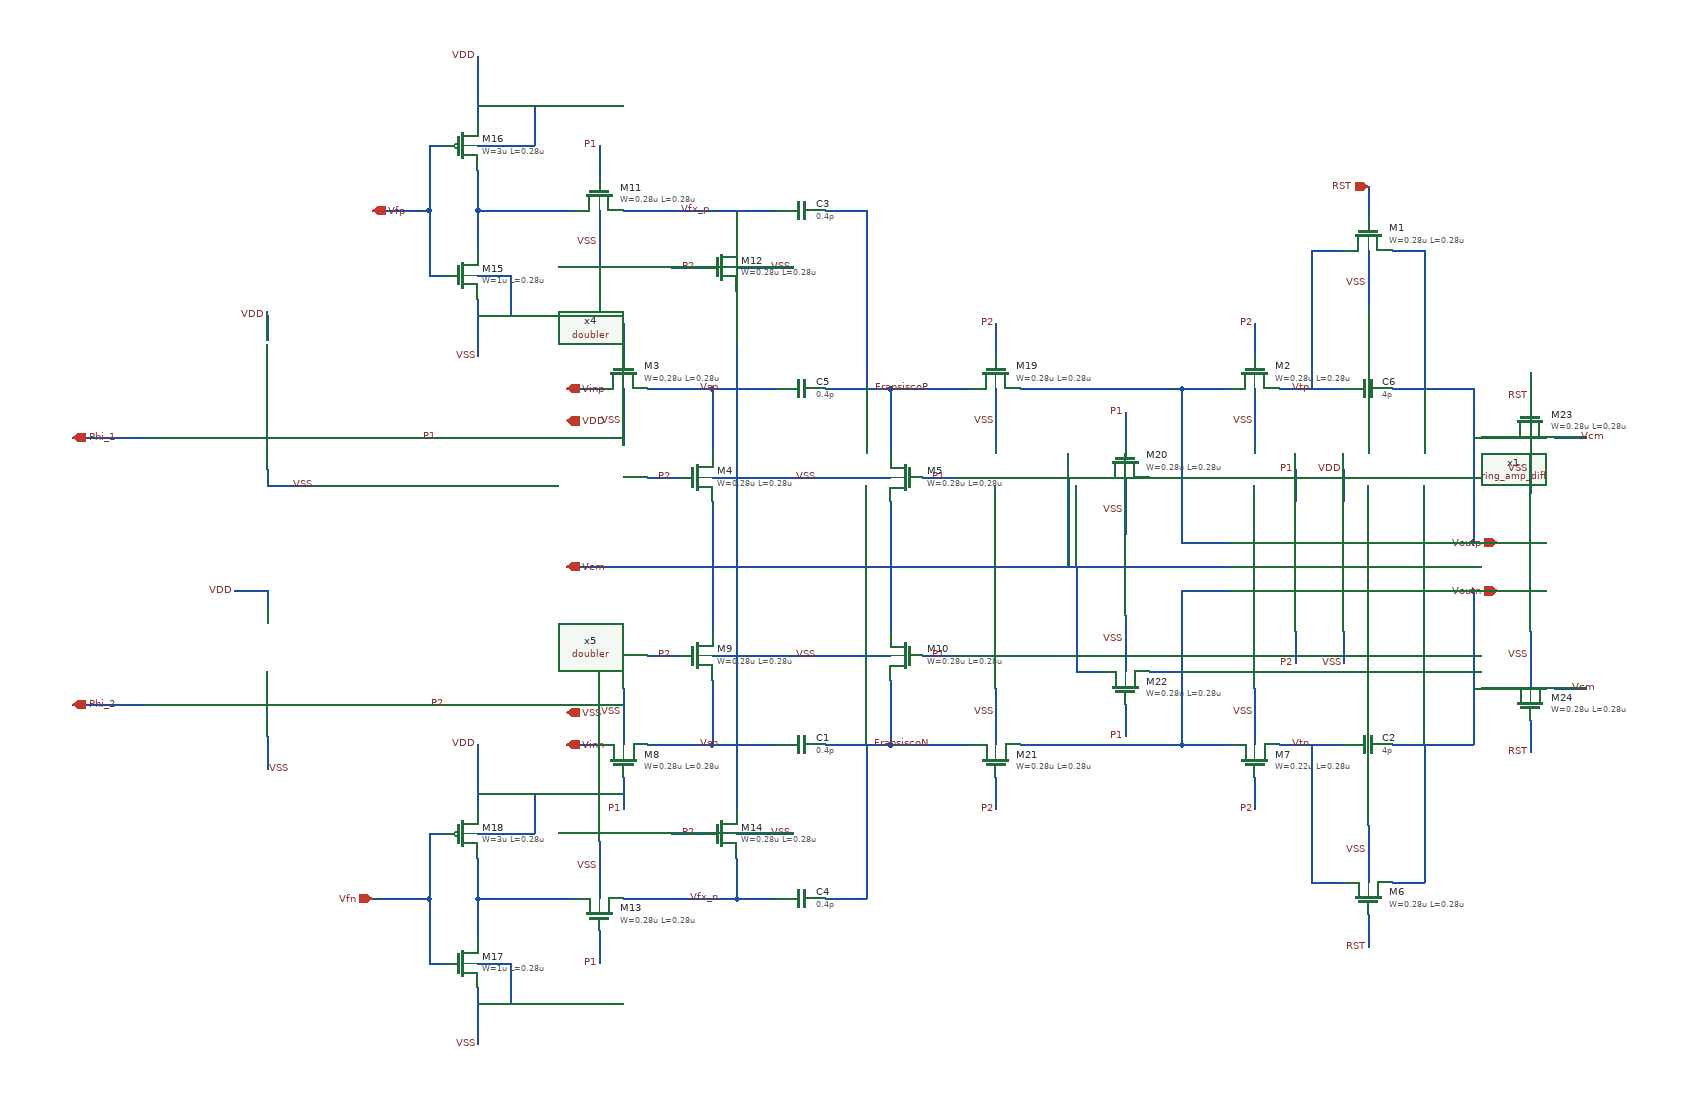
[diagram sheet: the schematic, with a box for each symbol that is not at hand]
v {xschem version=3.4.8RC file_version=1.3}
G {}
K {}
V {}
S {}
F {}
E {}
N 1190 -770 1190 -730 {lab=P1}
N 1250 -770 1250 -730 {lab=VDD}
N 1190 -570 1190 -530 {lab=P2}
N 1250 -570 1250 -530 {lab=VSS}
N 530 -650 1110 -650 {lab=Vcm}
N 470 -730 470 -690 {lab=Vcm}
N 690 -730 690 -690 {lab=Vcm}
N 470 -870 470 -790 {lab=Vsp}
N 690 -830 690 -790 {lab=FransiscoP}
N 610 -870 690 -870 {lab=FransiscoP}
N 470 -870 550 -870 {lab=Vsp}
N 390 -760 430 -760 {lab=P2}
N 390 -870 470 -870 {lab=Vsp}
N 290 -870 330 -870 {lab=Vinp}
N 360 -870 360 -800 {lab=VSS}
N 360 -950 360 -910 {lab=P1}
N 730 -760 770 -760 {lab=P1}
N 1140 -870 1140 -800 {lab=VSS}
N 690 -870 770 -870 {lab=FransiscoP}
N 1010 -870 1050 -870 {lab=#net1}
N 1050 -790 1050 -680 {lab=#net1}
N 470 -690 470 -650 {lab=Vcm}
N 690 -690 690 -650 {lab=Vcm}
N 690 -870 690 -830 {lab=FransiscoP}
N 1050 -870 1050 -790 {lab=#net1}
N 1050 -870 1090 -870 {lab=#net1}
N 1170 -870 1250 -870 {lab=Vtp}
N 1210 -1040 1210 -870 {lab=Vtp}
N 1210 -1040 1240 -1040 {lab=Vtp}
N 1140 -950 1140 -910 {lab=P2}
N 1280 -1120 1280 -1080 {lab=RST}
N 1370 -680 1410 -680 {lab=Voutp}
N 1410 -870 1410 -680 {lab=Voutp}
N 1330 -870 1410 -870 {lab=Voutp}
N 1310 -870 1330 -870 {lab=Voutp}
N 1240 -1040 1250 -1040 {lab=Vtp}
N 1310 -1040 1350 -1040 {lab=Voutp}
N 1350 -1040 1350 -870 {lab=Voutp}
N 1090 -870 1110 -870 {lab=#net1}
N 470 -760 690 -760 {lab=VSS}
N 470 -610 470 -570 {lab=Vcm}
N 690 -610 690 -570 {lab=Vcm}
N 470 -510 470 -430 {lab=Vsn}
N 690 -510 690 -470 {lab=FransiscoN}
N 610 -430 690 -430 {lab=FransiscoN}
N 470 -430 550 -430 {lab=Vsn}
N 390 -540 430 -540 {lab=P2}
N 390 -430 470 -430 {lab=Vsn}
N 290 -430 330 -430 {lab=Vinn}
N 360 -500 360 -430 {lab=VSS}
N 360 -390 360 -350 {lab=P1}
N 730 -540 770 -540 {lab=P1}
N 1140 -500 1140 -430 {lab=VSS}
N 690 -430 770 -430 {lab=FransiscoN}
N 1050 -620 1050 -510 {lab=#net2}
N 470 -650 470 -610 {lab=Vcm}
N 690 -650 690 -610 {lab=Vcm}
N 690 -470 690 -430 {lab=FransiscoN}
N 1050 -510 1050 -430 {lab=#net2}
N 1050 -430 1090 -430 {lab=#net2}
N 1170 -430 1250 -430 {lab=Vtn}
N 1210 -430 1210 -260 {lab=Vtn}
N 1210 -260 1240 -260 {lab=Vtn}
N 1140 -390 1140 -350 {lab=P2}
N 1280 -220 1280 -180 {lab=RST}
N 1370 -620 1410 -620 {lab=Voutn}
N 1410 -620 1410 -430 {lab=Voutn}
N 1330 -430 1410 -430 {lab=Voutn}
N 1310 -430 1330 -430 {lab=Voutn}
N 1240 -260 1250 -260 {lab=Vtn}
N 1310 -260 1350 -260 {lab=Voutn}
N 1350 -430 1350 -260 {lab=Voutn}
N 1090 -430 1110 -430 {lab=#net2}
N 470 -540 690 -540 {lab=VSS}
N 1410 -680 1440 -680 {lab=Voutp}
N 1410 -620 1440 -620 {lab=Voutn}
N 1280 -1040 1280 -970 {lab=VSS}
N 1280 -330 1280 -260 {lab=VSS}
N 180 -1280 180 -1240 {lab=VDD}
N 180 -950 180 -910 {lab=VSS}
N 50 -1090 120 -1090 {lab=Vfp}
N 360 -1090 440 -1090 {lab=Vfx_p}
N 260 -1090 300 -1090 {lab=#net3}
N 330 -1090 330 -1020 {lab=VSS}
N 330 -1170 330 -1130 {lab=P1}
N 420 -1020 460 -1020 {lab=P2}
N 440 -1090 550 -1090 {lab=Vfx_p}
N 500 -1090 500 -1050 {lab=Vfx_p}
N 50 -240 120 -240 {lab=Vfn}
N 260 -240 300 -240 {lab=#net4}
N 330 -310 330 -240 {lab=VSS}
N 330 -200 330 -160 {lab=P1}
N 420 -320 460 -320 {lab=P2}
N 500 -290 500 -240 {lab=Vfx_n}
N 500 -240 550 -240 {lab=Vfx_n}
N 500 -240 550 -240 {lab=Vfx_n}
N 360 -240 500 -240 {lab=Vfx_n}
N 500 -320 570 -320 {lab=VSS}
N 500 -1020 570 -1020 {lab=VSS}
N -290 -810 -230 -810 {lab=Phi_1}
N -290 -480 -230 -480 {lab=Phi_2}
N -80 -440 -80 -400 {lab=VSS}
N -80 -620 -80 -600 {lab=VDD}
N -120 -620 -80 -620 {lab=VDD}
N -80 -770 -80 -750 {lab=VSS}
N -80 -750 -30 -750 {lab=VSS}
N -80 -960 -80 -930 {lab=VDD}
N 70 -810 130 -810 {lab=P1}
N 70 -480 130 -480 {lab=P2}
N -320 -810 -290 -810 {lab=Phi_1}
N -320 -480 -290 -480 {lab=Phi_2}
N 180 -1240 180 -1200 {lab=VDD}
N 180 -1170 240 -1170 {lab=VDD}
N 240 -1170 250 -1170 {lab=VDD}
N 250 -1220 250 -1170 {lab=VDD}
N 180 -1220 250 -1220 {lab=VDD}
N 180 -1140 180 -1090 {lab=#net3}
N 180 -1090 260 -1090 {lab=#net3}
N 180 -1090 180 -1040 {lab=#net3}
N 120 -1010 140 -1010 {lab=Vfp}
N 120 -1090 120 -1010 {lab=Vfp}
N 120 -1170 120 -1090 {lab=Vfp}
N 120 -1170 140 -1170 {lab=Vfp}
N 180 -1010 220 -1010 {lab=VSS}
N 220 -1010 220 -960 {lab=VSS}
N 180 -960 220 -960 {lab=VSS}
N 180 -980 180 -950 {lab=VSS}
N 180 -430 180 -390 {lab=VDD}
N 180 -100 180 -60 {lab=VSS}
N 180 -390 180 -350 {lab=VDD}
N 180 -320 240 -320 {lab=VDD}
N 240 -320 250 -320 {lab=VDD}
N 250 -370 250 -320 {lab=VDD}
N 180 -370 250 -370 {lab=VDD}
N 180 -290 180 -240 {lab=#net4}
N 180 -240 260 -240 {lab=#net4}
N 180 -240 180 -190 {lab=#net4}
N 120 -160 140 -160 {lab=Vfn}
N 120 -240 120 -160 {lab=Vfn}
N 120 -320 120 -240 {lab=Vfn}
N 120 -320 140 -320 {lab=Vfn}
N 180 -160 220 -160 {lab=VSS}
N 220 -160 220 -110 {lab=VSS}
N 180 -110 220 -110 {lab=VSS}
N 180 -130 180 -100 {lab=VSS}
N 1050 -680 1070 -680 {lab=#net1}
N 1070 -620 1110 -620 {lab=#net2}
N 1090 -680 1110 -680 {lab=#net1}
N 1050 -620 1070 -620 {lab=#net2}
N 1070 -680 1090 -680 {lab=#net1}
N 500 -990 500 -650 {lab=Vcm}
N 610 -1090 660 -1090 {lab=FransiscoP}
N 660 -1090 660 -870 {lab=FransiscoP}
N 500 -650 500 -350 {lab=Vcm}
N 610 -240 660 -240 {lab=FransiscoN}
N 660 -430 660 -240 {lab=FransiscoN}
N 290 -650 530 -650 {lab=Vcm}
N 820 -870 820 -800 {lab=VSS}
N 820 -950 820 -910 {lab=P2}
N 770 -870 790 -870 {lab=FransiscoP}
N 850 -870 1010 -870 {lab=#net1}
N 910 -760 950 -760 {lab=Vcm}
N 980 -760 980 -690 {lab=VSS}
N 980 -840 980 -800 {lab=P1}
N 1010 -760 1050 -760 {lab=#net1}
N 910 -760 910 -650 {lab=Vcm}
N 820 -500 820 -430 {lab=VSS}
N 820 -390 820 -350 {lab=P2}
N 770 -430 790 -430 {lab=FransiscoN}
N 850 -430 1020 -430 {lab=#net2}
N 980 -590 980 -520 {lab=VSS}
N 980 -480 980 -440 {lab=P1}
N 1010 -520 1050 -520 {lab=#net2}
N 920 -520 950 -520 {lab=Vcm}
N 920 -650 920 -520 {lab=Vcm}
N 1020 -430 1050 -430 {lab=#net2}
N 1410 -810 1440 -810 {lab=Voutp}
N 1480 -890 1480 -850 {lab=RST}
N 1440 -810 1450 -810 {lab=Voutp}
N 1510 -810 1550 -810 {lab=Vcm}
N 1480 -810 1480 -740 {lab=VSS}
N 1410 -500 1440 -500 {lab=Voutn}
N 1480 -460 1480 -420 {lab=RST}
N 1440 -500 1450 -500 {lab=Voutn}
N 1510 -500 1550 -500 {lab=#net5}
N 1480 -570 1480 -500 {lab=VSS}
C {title.sym} 200 0 0 0 {name=l1 author="Onchip"}
C {symbols/nfet_03v3.sym} 1280 -1060 1 0 {name=M1
L=0.28u
W=0.28u
nf=1
m=1
ad="'int((nf+1)/2) * W/nf * 0.18u'"
pd="'2*int((nf+1)/2) * (W/nf + 0.18u)'"
as="'int((nf+2)/2) * W/nf * 0.18u'"
ps="'2*int((nf+2)/2) * (W/nf + 0.18u)'"
nrd="'0.18u / W'" nrs="'0.18u / W'"
sa=0 sb=0 sd=0
model=nfet_03v3
spiceprefix=X
}
C {symbols/nfet_03v3.sym} 1140 -890 1 0 {name=M2
L=0.28u
W=0.28u
nf=1
m=1
ad="'int((nf+1)/2) * W/nf * 0.18u'"
pd="'2*int((nf+1)/2) * (W/nf + 0.18u)'"
as="'int((nf+2)/2) * W/nf * 0.18u'"
ps="'2*int((nf+2)/2) * (W/nf + 0.18u)'"
nrd="'0.18u / W'" nrs="'0.18u / W'"
sa=0 sb=0 sd=0
model=nfet_03v3
spiceprefix=X
}
C {symbols/nfet_03v3.sym} 360 -890 1 0 {name=M3
L=0.28u
W=0.28u
nf=1
m=1
ad="'int((nf+1)/2) * W/nf * 0.18u'"
pd="'2*int((nf+1)/2) * (W/nf + 0.18u)'"
as="'int((nf+2)/2) * W/nf * 0.18u'"
ps="'2*int((nf+2)/2) * (W/nf + 0.18u)'"
nrd="'0.18u / W'" nrs="'0.18u / W'"
sa=0 sb=0 sd=0
model=nfet_03v3
spiceprefix=X
}
C {symbols/nfet_03v3.sym} 450 -760 0 0 {name=M4
L=0.28u
W=0.28u
nf=1
m=1
ad="'int((nf+1)/2) * W/nf * 0.18u'"
pd="'2*int((nf+1)/2) * (W/nf + 0.18u)'"
as="'int((nf+2)/2) * W/nf * 0.18u'"
ps="'2*int((nf+2)/2) * (W/nf + 0.18u)'"
nrd="'0.18u / W'" nrs="'0.18u / W'"
sa=0 sb=0 sd=0
model=nfet_03v3
spiceprefix=X
}
C {symbols/nfet_03v3.sym} 710 -760 0 1 {name=M5
L=0.28u
W=0.28u
nf=1
m=1
ad="'int((nf+1)/2) * W/nf * 0.18u'"
pd="'2*int((nf+1)/2) * (W/nf + 0.18u)'"
as="'int((nf+2)/2) * W/nf * 0.18u'"
ps="'2*int((nf+2)/2) * (W/nf + 0.18u)'"
nrd="'0.18u / W'" nrs="'0.18u / W'"
sa=0 sb=0 sd=0
model=nfet_03v3
spiceprefix=X
}
C {lab_wire.sym} 600 -760 0 0 {name=p1 sig_type=std_logic lab=VSS}
C {lab_wire.sym} 360 -950 3 0 {name=p2 sig_type=std_logic lab=P1}
C {lab_wire.sym} 760 -760 0 0 {name=p3 sig_type=std_logic lab=P1}
C {lab_wire.sym} 400 -760 0 1 {name=p4 sig_type=std_logic lab=P2
}
C {lab_wire.sym} 1140 -950 3 0 {name=p5 sig_type=std_logic lab=P2
}
C {symbols/nfet_03v3.sym} 1280 -240 1 1 {name=M6
L=0.28u
W=0.28u
nf=1
m=1
ad="'int((nf+1)/2) * W/nf * 0.18u'"
pd="'2*int((nf+1)/2) * (W/nf + 0.18u)'"
as="'int((nf+2)/2) * W/nf * 0.18u'"
ps="'2*int((nf+2)/2) * (W/nf + 0.18u)'"
nrd="'0.18u / W'" nrs="'0.18u / W'"
sa=0 sb=0 sd=0
model=nfet_03v3
spiceprefix=X
}
C {symbols/nfet_03v3.sym} 1140 -410 1 1 {name=M7
L=0.28u
W=0.22u
nf=1
m=1
ad="'int((nf+1)/2) * W/nf * 0.18u'"
pd="'2*int((nf+1)/2) * (W/nf + 0.18u)'"
as="'int((nf+2)/2) * W/nf * 0.18u'"
ps="'2*int((nf+2)/2) * (W/nf + 0.18u)'"
nrd="'0.18u / W'" nrs="'0.18u / W'"
sa=0 sb=0 sd=0
model=nfet_03v3
spiceprefix=X
}
C {symbols/nfet_03v3.sym} 360 -410 1 1 {name=M8
L=0.28u
W=0.28u
nf=1
m=1
ad="'int((nf+1)/2) * W/nf * 0.18u'"
pd="'2*int((nf+1)/2) * (W/nf + 0.18u)'"
as="'int((nf+2)/2) * W/nf * 0.18u'"
ps="'2*int((nf+2)/2) * (W/nf + 0.18u)'"
nrd="'0.18u / W'" nrs="'0.18u / W'"
sa=0 sb=0 sd=0
model=nfet_03v3
spiceprefix=X
}
C {symbols/nfet_03v3.sym} 450 -540 2 1 {name=M9
L=0.28u
W=0.28u
nf=1
m=1
ad="'int((nf+1)/2) * W/nf * 0.18u'"
pd="'2*int((nf+1)/2) * (W/nf + 0.18u)'"
as="'int((nf+2)/2) * W/nf * 0.18u'"
ps="'2*int((nf+2)/2) * (W/nf + 0.18u)'"
nrd="'0.18u / W'" nrs="'0.18u / W'"
sa=0 sb=0 sd=0
model=nfet_03v3
spiceprefix=X
}
C {symbols/nfet_03v3.sym} 710 -540 2 0 {name=M10
L=0.28u
W=0.28u
nf=1
m=1
ad="'int((nf+1)/2) * W/nf * 0.18u'"
pd="'2*int((nf+1)/2) * (W/nf + 0.18u)'"
as="'int((nf+2)/2) * W/nf * 0.18u'"
ps="'2*int((nf+2)/2) * (W/nf + 0.18u)'"
nrd="'0.18u / W'" nrs="'0.18u / W'"
sa=0 sb=0 sd=0
model=nfet_03v3
spiceprefix=X
}
C {lab_wire.sym} 600 -540 2 1 {name=p7 sig_type=std_logic lab=VSS}
C {lab_wire.sym} 360 -350 3 1 {name=p8 sig_type=std_logic lab=P1}
C {lab_wire.sym} 760 -540 2 1 {name=p9 sig_type=std_logic lab=P1}
C {lab_wire.sym} 400 -540 2 0 {name=p10 sig_type=std_logic lab=P2
}
C {lab_wire.sym} 1140 -350 3 1 {name=p11 sig_type=std_logic lab=P2
}
C {lab_wire.sym} 1280 -180 3 1 {name=p12 sig_type=std_logic lab=RST
}
C {lab_wire.sym} 1190 -770 3 0 {name=p13 sig_type=std_logic lab=P1
}
C {lab_wire.sym} 1250 -770 3 0 {name=p14 sig_type=std_logic lab=VDD
}
C {lab_wire.sym} 1190 -530 3 1 {name=p15 sig_type=std_logic lab=P2


}
C {lab_wire.sym} 1250 -530 3 1 {name=p16 sig_type=std_logic lab=VSS
}
C {lab_wire.sym} 480 -870 0 0 {name=p17 sig_type=std_logic lab=Vsp}
C {lab_wire.sym} 1210 -870 0 0 {name=p18 sig_type=std_logic lab=Vtp}
C {lab_wire.sym} 480 -430 2 1 {name=p19 sig_type=std_logic lab=Vsn}
C {lab_wire.sym} 1210 -430 2 1 {name=p20 sig_type=std_logic lab=Vtn}
C {iopin.sym} 290 -870 0 1 {name=p21 lab=Vinp}
C {iopin.sym} 290 -650 0 1 {name=p22 lab=Vcm}
C {iopin.sym} 290 -430 0 1 {name=p23 lab=Vinn}
C {iopin.sym} 1440 -680 0 0 {name=p24 lab=Voutp}
C {iopin.sym} 1440 -620 0 0 {name=p25 lab=Voutn}
C {iopin.sym} 1280 -1120 3 0 {name=p26 lab=RST}
C {iopin.sym} 290 -830 0 1 {name=p6 lab=VDD}
C {iopin.sym} -320 -810 0 1 {name=p27 lab=Phi_1}
C {iopin.sym} 290 -470 0 1 {name=p28 lab=VSS}
C {iopin.sym} -320 -480 0 1 {name=p29 lab=Phi_2}
C {lab_wire.sym} 1140 -470 3 1 {name=p30 sig_type=std_logic lab=VSS
}
C {lab_wire.sym} 360 -470 3 1 {name=p31 sig_type=std_logic lab=VSS
}
C {lab_wire.sym} 360 -830 3 0 {name=p32 sig_type=std_logic lab=VSS
}
C {lab_wire.sym} 1140 -830 3 0 {name=p33 sig_type=std_logic lab=VSS
}
C {lab_wire.sym} 1280 -1000 3 0 {name=p34 sig_type=std_logic lab=VSS
}
C {lab_wire.sym} 1280 -300 3 1 {name=p35 sig_type=std_logic lab=VSS
}
C {capa.sym} 580 -870 1 0 {name=C5
m=1
value=0.4p
footprint=1206
device="ceramic capacitor"}
C {capa.sym} 1280 -870 1 0 {name=C6
m=1
value=4p
footprint=1206
device="ceramic capacitor"}
C {capa.sym} 580 -430 1 0 {name=C1
m=1
value=0.4p
footprint=1206
device="ceramic capacitor"}
C {capa.sym} 1280 -430 1 0 {name=C2
m=1
value=4p
footprint=1206
device="ceramic capacitor"}
C {lab_wire.sym} 740 -870 0 0 {name=p36 sig_type=std_logic lab=FransiscoP}
C {lab_wire.sym} 740 -430 0 0 {name=p37 sig_type=std_logic lab=FransiscoN}
C {DS_modulator/ring_amp_diff/xschem/ring_amp_diff.sym} 1220 -650 0 0 {name=x1}
C {capa.sym} 580 -1090 1 0 {name=C3
m=1
value=0.4p
footprint=1206
device="ceramic capacitor"}
C {lab_wire.sym} 180 -1280 3 0 {name=p38 sig_type=std_logic lab=VDD
}
C {lab_wire.sym} 180 -910 3 1 {name=p39 sig_type=std_logic lab=VSS
}
C {symbols/nfet_03v3.sym} 330 -1110 1 0 {name=M11
L=0.28u
W=0.28u
nf=1
m=1
ad="'int((nf+1)/2) * W/nf * 0.18u'"
pd="'2*int((nf+1)/2) * (W/nf + 0.18u)'"
as="'int((nf+2)/2) * W/nf * 0.18u'"
ps="'2*int((nf+2)/2) * (W/nf + 0.18u)'"
nrd="'0.18u / W'" nrs="'0.18u / W'"
sa=0 sb=0 sd=0
model=nfet_03v3
spiceprefix=X
}
C {lab_wire.sym} 330 -1170 3 0 {name=p40 sig_type=std_logic lab=P1}
C {lab_wire.sym} 330 -1050 3 0 {name=p41 sig_type=std_logic lab=VSS
}
C {symbols/nfet_03v3.sym} 480 -1020 0 0 {name=M12
L=0.28u
W=0.28u
nf=1
m=1
ad="'int((nf+1)/2) * W/nf * 0.18u'"
pd="'2*int((nf+1)/2) * (W/nf + 0.18u)'"
as="'int((nf+2)/2) * W/nf * 0.18u'"
ps="'2*int((nf+2)/2) * (W/nf + 0.18u)'"
nrd="'0.18u / W'" nrs="'0.18u / W'"
sa=0 sb=0 sd=0
model=nfet_03v3
spiceprefix=X
}
C {lab_wire.sym} 430 -1020 0 1 {name=p42 sig_type=std_logic lab=P2
}
C {iopin.sym} 50 -1090 0 1 {name=p43 lab=Vfp}
C {symbols/nfet_03v3.sym} 330 -220 1 1 {name=M13
L=0.28u
W=0.28u
nf=1
m=1
ad="'int((nf+1)/2) * W/nf * 0.18u'"
pd="'2*int((nf+1)/2) * (W/nf + 0.18u)'"
as="'int((nf+2)/2) * W/nf * 0.18u'"
ps="'2*int((nf+2)/2) * (W/nf + 0.18u)'"
nrd="'0.18u / W'" nrs="'0.18u / W'"
sa=0 sb=0 sd=0
model=nfet_03v3
spiceprefix=X
}
C {lab_wire.sym} 330 -160 3 1 {name=p46 sig_type=std_logic lab=P1}
C {lab_wire.sym} 330 -280 3 1 {name=p47 sig_type=std_logic lab=VSS
}
C {iopin.sym} 50 -240 2 0 {name=p48 lab=Vfn}
C {capa.sym} 580 -240 1 0 {name=C4
m=1
value=0.4p
footprint=1206
device="ceramic capacitor"}
C {symbols/nfet_03v3.sym} 480 -320 2 1 {name=M14
L=0.28u
W=0.28u
nf=1
m=1
ad="'int((nf+1)/2) * W/nf * 0.18u'"
pd="'2*int((nf+1)/2) * (W/nf + 0.18u)'"
as="'int((nf+2)/2) * W/nf * 0.18u'"
ps="'2*int((nf+2)/2) * (W/nf + 0.18u)'"
nrd="'0.18u / W'" nrs="'0.18u / W'"
sa=0 sb=0 sd=0
model=nfet_03v3
spiceprefix=X
}
C {lab_wire.sym} 430 -320 2 0 {name=p49 sig_type=std_logic lab=P2
}
C {lab_wire.sym} 540 -320 0 1 {name=p50 sig_type=std_logic lab=VSS
}
C {lab_wire.sym} 540 -1020 0 1 {name=p51 sig_type=std_logic lab=VSS
}
C {DS_modulator/doubler/xschem/doubler.sym} -80 -850 0 0 {name=x4}
C {DS_modulator/doubler/xschem/doubler.sym} -80 -520 0 0 {name=x5}
C {lab_wire.sym} -120 -620 0 0 {name=p54 sig_type=std_logic lab=VDD}
C {lab_wire.sym} -50 -750 0 1 {name=p55 sig_type=std_logic lab=VSS}
C {lab_wire.sym} -80 -960 0 0 {name=p56 sig_type=std_logic lab=VDD}
C {lab_wire.sym} -80 -400 0 1 {name=p57 sig_type=std_logic lab=VSS}
C {lab_wire.sym} 110 -810 0 1 {name=p58 sig_type=std_logic lab=P1

}
C {lab_wire.sym} 120 -480 0 1 {name=p59 sig_type=std_logic lab=P2}
C {lab_wire.sym} 470 -1090 0 0 {name=p60 sig_type=std_logic lab=Vfx_p}
C {lab_wire.sym} 480 -240 0 0 {name=p61 sig_type=std_logic lab=Vfx_n}
C {symbols/nfet_03v3.sym} 160 -1010 0 0 {name=M15
L=0.28u
W=1u
nf=1
m=8
ad="'int((nf+1)/2) * W/nf * 0.18u'"
pd="'2*int((nf+1)/2) * (W/nf + 0.18u)'"
as="'int((nf+2)/2) * W/nf * 0.18u'"
ps="'2*int((nf+2)/2) * (W/nf + 0.18u)'"
nrd="'0.18u / W'" nrs="'0.18u / W'"
sa=0 sb=0 sd=0
model=nfet_03v3
spiceprefix=X
}
C {symbols/pfet_03v3.sym} 160 -1170 0 0 {name=M16
L=0.28u
W=3u
nf=1
m=8
ad="'int((nf+1)/2) * W/nf * 0.18u'"
pd="'2*int((nf+1)/2) * (W/nf + 0.18u)'"
as="'int((nf+2)/2) * W/nf * 0.18u'"
ps="'2*int((nf+2)/2) * (W/nf + 0.18u)'"
nrd="'0.18u / W'" nrs="'0.18u / W'"
sa=0 sb=0 sd=0
model=pfet_03v3
spiceprefix=X
}
C {lab_wire.sym} 180 -430 3 0 {name=p44 sig_type=std_logic lab=VDD
}
C {lab_wire.sym} 180 -60 3 1 {name=p45 sig_type=std_logic lab=VSS
}
C {symbols/nfet_03v3.sym} 160 -160 0 0 {name=M17
L=0.28u
W=1u
nf=1
m=8
ad="'int((nf+1)/2) * W/nf * 0.18u'"
pd="'2*int((nf+1)/2) * (W/nf + 0.18u)'"
as="'int((nf+2)/2) * W/nf * 0.18u'"
ps="'2*int((nf+2)/2) * (W/nf + 0.18u)'"
nrd="'0.18u / W'" nrs="'0.18u / W'"
sa=0 sb=0 sd=0
model=nfet_03v3
spiceprefix=X
}
C {symbols/pfet_03v3.sym} 160 -320 0 0 {name=M18
L=0.28u
W=3u
nf=1
m=8
ad="'int((nf+1)/2) * W/nf * 0.18u'"
pd="'2*int((nf+1)/2) * (W/nf + 0.18u)'"
as="'int((nf+2)/2) * W/nf * 0.18u'"
ps="'2*int((nf+2)/2) * (W/nf + 0.18u)'"
nrd="'0.18u / W'" nrs="'0.18u / W'"
sa=0 sb=0 sd=0
model=pfet_03v3
spiceprefix=X
}
C {symbols/nfet_03v3.sym} 820 -890 1 0 {name=M19
L=0.28u
W=0.28u
nf=1
m=1
ad="'int((nf+1)/2) * W/nf * 0.18u'"
pd="'2*int((nf+1)/2) * (W/nf + 0.18u)'"
as="'int((nf+2)/2) * W/nf * 0.18u'"
ps="'2*int((nf+2)/2) * (W/nf + 0.18u)'"
nrd="'0.18u / W'" nrs="'0.18u / W'"
sa=0 sb=0 sd=0
model=nfet_03v3
spiceprefix=X
}
C {lab_wire.sym} 820 -950 3 0 {name=p52 sig_type=std_logic lab=P2
}
C {lab_wire.sym} 820 -830 3 0 {name=p53 sig_type=std_logic lab=VSS
}
C {symbols/nfet_03v3.sym} 980 -780 1 0 {name=M20
L=0.28u
W=0.28u
nf=1
m=1
ad="'int((nf+1)/2) * W/nf * 0.18u'"
pd="'2*int((nf+1)/2) * (W/nf + 0.18u)'"
as="'int((nf+2)/2) * W/nf * 0.18u'"
ps="'2*int((nf+2)/2) * (W/nf + 0.18u)'"
nrd="'0.18u / W'" nrs="'0.18u / W'"
sa=0 sb=0 sd=0
model=nfet_03v3
spiceprefix=X
}
C {lab_wire.sym} 980 -840 3 0 {name=p62 sig_type=std_logic lab=P1}
C {lab_wire.sym} 980 -720 3 0 {name=p63 sig_type=std_logic lab=VSS
}
C {symbols/nfet_03v3.sym} 820 -410 1 1 {name=M21
L=0.28u
W=0.28u
nf=1
m=1
ad="'int((nf+1)/2) * W/nf * 0.18u'"
pd="'2*int((nf+1)/2) * (W/nf + 0.18u)'"
as="'int((nf+2)/2) * W/nf * 0.18u'"
ps="'2*int((nf+2)/2) * (W/nf + 0.18u)'"
nrd="'0.18u / W'" nrs="'0.18u / W'"
sa=0 sb=0 sd=0
model=nfet_03v3
spiceprefix=X
}
C {lab_wire.sym} 820 -350 3 1 {name=p64 sig_type=std_logic lab=P2
}
C {lab_wire.sym} 820 -470 3 1 {name=p65 sig_type=std_logic lab=VSS
}
C {symbols/nfet_03v3.sym} 980 -500 1 1 {name=M22
L=0.28u
W=0.28u
nf=1
m=1
ad="'int((nf+1)/2) * W/nf * 0.18u'"
pd="'2*int((nf+1)/2) * (W/nf + 0.18u)'"
as="'int((nf+2)/2) * W/nf * 0.18u'"
ps="'2*int((nf+2)/2) * (W/nf + 0.18u)'"
nrd="'0.18u / W'" nrs="'0.18u / W'"
sa=0 sb=0 sd=0
model=nfet_03v3
spiceprefix=X
}
C {lab_wire.sym} 980 -440 3 1 {name=p66 sig_type=std_logic lab=P1}
C {lab_wire.sym} 980 -560 3 1 {name=p67 sig_type=std_logic lab=VSS
}
C {symbols/nfet_03v3.sym} 1480 -830 1 0 {name=M23
L=0.28u
W=0.28u
nf=1
m=1
ad="'int((nf+1)/2) * W/nf * 0.18u'"
pd="'2*int((nf+1)/2) * (W/nf + 0.18u)'"
as="'int((nf+2)/2) * W/nf * 0.18u'"
ps="'2*int((nf+2)/2) * (W/nf + 0.18u)'"
nrd="'0.18u / W'" nrs="'0.18u / W'"
sa=0 sb=0 sd=0
model=nfet_03v3
spiceprefix=X
}
C {lab_wire.sym} 1480 -770 3 0 {name=p69 sig_type=std_logic lab=VSS
}
C {symbols/nfet_03v3.sym} 1480 -480 1 1 {name=M24
L=0.28u
W=0.28u
nf=1
m=1
ad="'int((nf+1)/2) * W/nf * 0.18u'"
pd="'2*int((nf+1)/2) * (W/nf + 0.18u)'"
as="'int((nf+2)/2) * W/nf * 0.18u'"
ps="'2*int((nf+2)/2) * (W/nf + 0.18u)'"
nrd="'0.18u / W'" nrs="'0.18u / W'"
sa=0 sb=0 sd=0
model=nfet_03v3
spiceprefix=X
}
C {lab_wire.sym} 1480 -420 3 1 {name=p68 sig_type=std_logic lab=RST
}
C {lab_wire.sym} 1480 -540 3 1 {name=p70 sig_type=std_logic lab=VSS
}
C {lab_wire.sym} 1480 -860 3 1 {name=p71 sig_type=std_logic lab=RST
}
C {lab_wire.sym} 1540 -810 0 1 {name=p72 sig_type=std_logic lab=Vcm
}
C {lab_wire.sym} 1530 -500 0 1 {name=p73 sig_type=std_logic lab=Vcm
}
